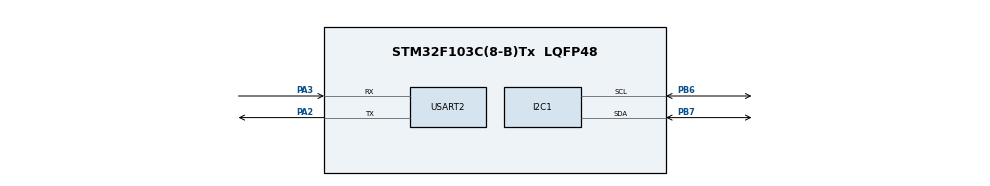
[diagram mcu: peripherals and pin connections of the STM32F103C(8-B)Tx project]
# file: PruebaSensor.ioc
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Mcu.Family=STM32F1
Mcu.Name=STM32F103C(8-B)Tx
Mcu.Package=LQFP48
NVIC.PriorityGroup=NVIC_PRIORITYGROUP_4
PA2.Mode=Asynchronous
PA2.Signal=USART2_TX
PA3.Mode=Asynchronous
PA3.Signal=USART2_RX
PB6.Mode=I2C
PB6.Signal=I2C1_SCL
PB7.Mode=I2C
PB7.Signal=I2C1_SDA
PD0-OSC_IN.Mode=HSE-External-Oscillator
PD0-OSC_IN.Signal=RCC_OSC_IN
PD1-OSC_OUT.Mode=HSE-External-Oscillator
PD1-OSC_OUT.Signal=RCC_OSC_OUT
ProjectManager.HeapSize=0x200
ProjectManager.StackSize=0x400
ProjectManager.TargetToolchain=MDK-ARM V5
RCC.APB1Freq_Value=8000000
RCC.APB2Freq_Value=8000000
USART2.VirtualMode=VM_ASYNC
VP_SYS_VS_ND.Mode=No_Debug
board=custom

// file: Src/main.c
#include "main.h"
#include "stm32f1xx_hal.h"
#include "math.h"

I2C_HandleTypeDef hi2c1;
UART_HandleTypeDef huart2;

/* USER CODE BEGIN PV */
/* Private variables ---------------------------------------------------------*/

/* USER CODE END PV */

void SystemClock_Config(void);
static void MX_GPIO_Init(void);
static void MX_I2C1_Init(void);
static void MX_USART2_UART_Init(void);

char dataOut[100];

	#define address 0xD0	//dir
	#define RAD_A_DEG		57.2957
	#define A_R 16384.0//Se supone que da 16 bits en cada uno de los ejes, en la hoja de datos, divide esos 32768/2g esto es por default
	#define G_R 131.0		//32768/250
	uint8_t i, i2cBuf[8];
	int16_t AcX, AcY, AcZ, GyX, GyY,GyZ;
	float Acc[3]; 	//Angulo X --->[0]  Angulo Y---->[1]  Angulo Z---->[2]
	float Gy[3];

	float Angulo[3];				//Ángulo final
	float dt;
	long tiempo_Ant;

int main(void)
{

  /* MCU Configuration----------------------------------------------------------*/

  /* Reset of all peripherals, Initializes the Flash interface and the Systick. */
  HAL_Init();

  /* Configure the system clock */
  SystemClock_Config();

  /* Initialize all configured peripherals */
  MX_GPIO_Init();
  MX_I2C1_Init();
  MX_USART2_UART_Init();

 //Saber dirección del dispositivo
 for(i=0;i<255;i++){
		if(HAL_I2C_IsDeviceReady(&hi2c1,i,1,10)==HAL_OK){
				HAL_GPIO_TogglePin(GPIOC,GPIO_PIN_13);
			break;
		}
 }
 //DIRECCION ES i =

	i2cBuf[0]=0x6B;	//POWER del MPU 6B->0 para reinicializar el sensor
	i2cBuf[1]=0x00;

 HAL_I2C_Master_Transmit(&hi2c1,i,i2cBuf,2,10);
 //Prueba de lectura.................
	i2cBuf[0]=28;	//POWER del MPU 6B->0 para reinicializar el sensor
	i2cBuf[1]=0x08;		//8g 16g 32g
	HAL_I2C_Master_Transmit(&hi2c1,i,i2cBuf,2,10);

// //leemos el sensor
//
// HAL_I2C_Master_Transmit(&hi2c1,i,i2cBuf,1,10);
// i2cBuf[1]=0;		//Si hay que borrarla par ver que si tiene un 8, para probar
// HAL_I2C_Master_Receive(&hi2c1,i,&i2cBuf[1],1,100); //en i2cBuf[1] tiene que estar los 8 bits que transmiti

 //..................................

  while (1)
  {
		//Se escribe la dirección de los registros a leer, en este caso 3B para aceleraciones en los tres ejes
		i2cBuf[0]=0x3B;
		HAL_I2C_Master_Transmit(&hi2c1,i,i2cBuf,1,10);

		HAL_I2C_Master_Receive(&hi2c1,i,&i2cBuf[1],6,100);
		AcX= i2cBuf[1]<<8|i2cBuf[2];					//Concatenación de bits, van a ser 16 bits, se declaran arriba
		AcY= i2cBuf[3]<<8|i2cBuf[4];
		AcZ= i2cBuf[5]<<8|i2cBuf[6];

		Acc[0]=atan(-1*(AcX/A_R)/sqrt(pow(AcY/A_R,2)+pow(AcZ/A_R,2)))*RAD_A_DEG;
		Acc[1]=atan((AcY/A_R)/sqrt(pow(AcX/A_R,2)+pow(AcZ/A_R,2)))*RAD_A_DEG;

		i2cBuf[0]=0x43;			//Para leer los valores del giroscopio en X Y Z
		HAL_I2C_Master_Transmit(&hi2c1,i,i2cBuf,1,10);
		HAL_I2C_Master_Receive(&hi2c1,i,&i2cBuf[1],6,10);

		GyX= i2cBuf[1]<<8|i2cBuf[2];					//Concatenación de bits, van a ser 16 bits, se declaran arriba
		GyY= i2cBuf[3]<<8|i2cBuf[4];
		GyZ= i2cBuf[5]<<8|i2cBuf[6];
		Gy[0]=GyX/G_R;												//Recupero valores, esos valores están entre 250 y los guardamos aquí
		Gy[1]=GyY/G_R;												//para que me de grado por segundo directamente
		Gy[2]=GyZ/G_R;
		//Se va a crear una variable como la de ACC pero para el gyroscopio, se tiene que hacer para sacar el giro lo de una integral.
		//*******************************Obtención del ángulo**************************************************************************
		//Se utiliza el Systick

		dt=(HAL_GetTick()-tiempo_Ant)/1000;		//Te va a dar la cuenta en la que va, un registro que va a estar contando. Entre 1000 para que nos de en milisegundos
		tiempo_Ant=HAL_GetTick();						//Ya con esto se obtiene un diferencial, para calcular un ángulo, creamos un diferencial discreto
																				//Lleva paréntesis
//*********************Filtro complementario: calcula el ángulo con base al Acc y el Gy de cada eje
		Angulo[0]=0.98*(Angulo[0]+Gy[0]*dt)+ 0.02*Acc[0];				//Esta es la integral solita para el ángulo. Ángulo  del gyroscopio + angulo del acc = total
		Angulo[1]=0.98*(Angulo[1]+Gy[1]*dt)+ 0.02*Acc[0];
		Angulo[2]=Angulo[2]+Gy[2]*dt;

		sprintf(dataOut,"Angulo:%f\n",Angulo[0]);
		HAL_UART_Transmit(&huart2, dataOut,strlen(dataOut), 100);

		//**Acc--->ang x aceleracion;
		//Angulo---->accel+gyro

  }
}

void SystemClock_Config(void)
{

  RCC_OscInitTypeDef RCC_OscInitStruct;
  RCC_ClkInitTypeDef RCC_ClkInitStruct;

    /**Initializes the CPU, AHB and APB busses clocks
    */
  RCC_OscInitStruct.OscillatorType = RCC_OSCILLATORTYPE_HSE;
  RCC_OscInitStruct.HSEState = RCC_HSE_ON;
  RCC_OscInitStruct.HSEPredivValue = RCC_HSE_PREDIV_DIV1;
  RCC_OscInitStruct.HSIState = RCC_HSI_ON;
  RCC_OscInitStruct.PLL.PLLState = RCC_PLL_ON;
  RCC_OscInitStruct.PLL.PLLSource = RCC_PLLSOURCE_HSE;
  RCC_OscInitStruct.PLL.PLLMUL = RCC_PLL_MUL9;
  if (HAL_RCC_OscConfig(&RCC_OscInitStruct) != HAL_OK)
  {
    _Error_Handler(__FILE__, __LINE__);
  }

    /**Initializes the CPU, AHB and APB busses clocks
    */
  RCC_ClkInitStruct.ClockType = RCC_CLOCKTYPE_HCLK|RCC_CLOCKTYPE_SYSCLK
                              |RCC_CLOCKTYPE_PCLK1|RCC_CLOCKTYPE_PCLK2;
  RCC_ClkInitStruct.SYSCLKSource = RCC_SYSCLKSOURCE_PLLCLK;
  RCC_ClkInitStruct.AHBCLKDivider = RCC_SYSCLK_DIV1;
  RCC_ClkInitStruct.APB1CLKDivider = RCC_HCLK_DIV2;
  RCC_ClkInitStruct.APB2CLKDivider = RCC_HCLK_DIV1;

  if (HAL_RCC_ClockConfig(&RCC_ClkInitStruct, FLASH_LATENCY_2) != HAL_OK)
  {
    _Error_Handler(__FILE__, __LINE__);
  }

    /**Configure the Systick interrupt time
    */
  HAL_SYSTICK_Config(HAL_RCC_GetHCLKFreq()/1000);

    /**Configure the Systick
    */
  HAL_SYSTICK_CLKSourceConfig(SYSTICK_CLKSOURCE_HCLK);

  /* SysTick_IRQn interrupt configuration */
  HAL_NVIC_SetPriority(SysTick_IRQn, 0, 0);
}

static void MX_USART2_UART_Init(void)
{

  huart2.Instance = USART2;
  huart2.Init.BaudRate = 115200;
  huart2.Init.WordLength = UART_WORDLENGTH_8B;
  huart2.Init.StopBits = UART_STOPBITS_1;
  huart2.Init.Parity = UART_PARITY_NONE;
  huart2.Init.Mode = UART_MODE_TX_RX;
  huart2.Init.HwFlowCtl = UART_HWCONTROL_NONE;
  huart2.Init.OverSampling = UART_OVERSAMPLING_16;
  if (HAL_UART_Init(&huart2) != HAL_OK)
  {
    _Error_Handler(__FILE__, __LINE__);
  }

}

/* I2C2 init function */
static void MX_I2C1_Init(void)
{

  hi2c1.Instance = I2C1;
  hi2c1.Init.ClockSpeed = 400000;
  hi2c1.Init.DutyCycle = I2C_DUTYCYCLE_2;
  hi2c1.Init.OwnAddress1 = 0;
  hi2c1.Init.AddressingMode = I2C_ADDRESSINGMODE_7BIT;
  hi2c1.Init.DualAddressMode = I2C_DUALADDRESS_DISABLE;
  hi2c1.Init.OwnAddress2 = 0;
  hi2c1.Init.GeneralCallMode = I2C_GENERALCALL_DISABLE;
  hi2c1.Init.NoStretchMode = I2C_NOSTRETCH_DISABLE;
  if (HAL_I2C_Init(&hi2c1) != HAL_OK)
  {
    _Error_Handler(__FILE__, __LINE__);
  }

}

static void MX_GPIO_Init(void)
{

  GPIO_InitTypeDef GPIO_InitStruct;

  /* GPIO Ports Clock Enable */
  __HAL_RCC_GPIOC_CLK_ENABLE();
  __HAL_RCC_GPIOD_CLK_ENABLE();
  __HAL_RCC_GPIOB_CLK_ENABLE();
  __HAL_RCC_GPIOA_CLK_ENABLE();

  /*Configure GPIO pin Output Level */
  HAL_GPIO_WritePin(GPIOC, GPIO_PIN_13, GPIO_PIN_RESET);

  /*Configure GPIO pin : PC13 */
  GPIO_InitStruct.Pin = GPIO_PIN_13;
  GPIO_InitStruct.Mode = GPIO_MODE_OUTPUT_PP;
  GPIO_InitStruct.Pull = GPIO_NOPULL;
  GPIO_InitStruct.Speed = GPIO_SPEED_FREQ_LOW;
  HAL_GPIO_Init(GPIOC, &GPIO_InitStruct);

}

void _Error_Handler(char *file, int line)
{
  while(1)
  {
  }
}

/************************ (C) COPYRIGHT STMicroelectronics *****END OF FILE****/
